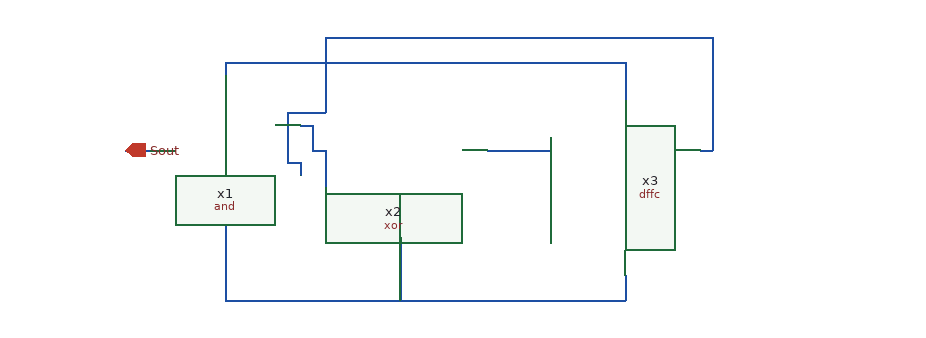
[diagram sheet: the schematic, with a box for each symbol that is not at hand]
v {xschem version=2.9.9 file_version=1.2 }
G {}
K {}
V {}
S {}
E {}
N 190 70 240 70 { lab=#net1}
N 240 60 240 70 { lab=#net1}
N 300 170 300 190 { lab=#net2}
N -20 190 300 190 { lab=#net2}
N -20 130 -20 190 { lab=#net2}
N 120 140 120 190 { lab=#net2}
N 120 0 300 -0 { lab=#net3}
N 300 -0 300 30 { lab=#net3}
N -20 -0 120 0 { lab=#net3}
N -20 -0 -20 10 { lab=#net3}
N 40 50 50 50 { lab=#net4}
N 50 50 50 70 { lab=#net4}
N 50 70 60 70 { lab=#net4}
N 60 70 60 100 { lab=#net4}
N 40 80 40 90 { lab=#net5}
N 30 80 40 80 { lab=#net5}
N 30 40 30 80 { lab=#net5}
N 30 40 60 40 { lab=#net5}
N 60 -20 60 40 { lab=#net5}
N 60 -20 370 -20 { lab=#net5}
N 370 -20 370 70 { lab=#net5}
N 360 70 370 70 { lab=#net5}
N -100 70 -80 70 { lab=xxx}
C {/home/eamta/eamta2021/sch/and/and.sym} -110 70 0 1 {name=x1}
C {/home/eamta/eamta2021/sch/xor/xor.sym} 210 60 0 0 {name=x2}
C {/home/eamta/eamta2021/sch/dffc/dffc.sym} 390 100 0 0 {name=x3}
C {opin.sym} -100 70 2 0 {name=p1 lab=Sout}
